VERSION 5.7 ;
  NOWIREEXTENSIONATPIN ON ;
  DIVIDERCHAR "/" ;
  BUSBITCHARS "[]" ;
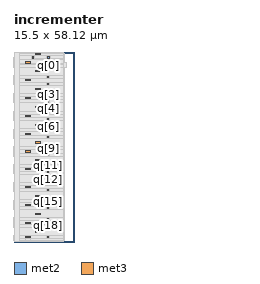
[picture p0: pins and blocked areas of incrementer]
MACRO incrementer
  CLASS BLOCK ;
  FOREIGN incrementer ;
  ORIGIN 0.000 0.000 ;
  SIZE 15.500 BY 58.120 ;
  PIN q[18]
    DIRECTION OUTPUT ;
    USE SIGNAL ;
    ANTENNAGATEAREA 0.235500 ;
    ANTENNADIFFAREA 1.339600 ;
    PORT
      LAYER met2 ;
        RECT 10.320 4.730 10.700 5.110 ;
    END
  END q[18]
  PIN q[19]
    DIRECTION OUTPUT ;
    USE SIGNAL ;
    ANTENNAGATEAREA 0.235500 ;
    ANTENNADIFFAREA 1.339600 ;
    PORT
      LAYER met2 ;
        RECT 10.320 1.330 10.700 1.710 ;
    END
  END q[19]
  PIN q[16]
    DIRECTION OUTPUT ;
    USE SIGNAL ;
    ANTENNAGATEAREA 0.235500 ;
    ANTENNADIFFAREA 1.339600 ;
    PORT
      LAYER met2 ;
        RECT 10.320 10.170 10.700 10.550 ;
    END
  END q[16]
  PIN q[17]
    DIRECTION OUTPUT ;
    USE SIGNAL ;
    ANTENNAGATEAREA 0.235500 ;
    ANTENNADIFFAREA 1.339600 ;
    PORT
      LAYER met2 ;
        RECT 10.320 6.770 10.700 7.150 ;
    END
  END q[17]
  PIN q[14]
    DIRECTION OUTPUT ;
    USE SIGNAL ;
    ANTENNAGATEAREA 0.235500 ;
    ANTENNADIFFAREA 1.339600 ;
    PORT
      LAYER met2 ;
        RECT 10.320 15.610 10.700 15.990 ;
    END
  END q[14]
  PIN q[15]
    DIRECTION OUTPUT ;
    USE SIGNAL ;
    ANTENNAGATEAREA 0.235500 ;
    ANTENNADIFFAREA 1.339600 ;
    PORT
      LAYER met2 ;
        RECT 10.320 12.210 10.700 12.590 ;
    END
  END q[15]
  PIN q[12]
    DIRECTION OUTPUT ;
    USE SIGNAL ;
    ANTENNAGATEAREA 0.235500 ;
    ANTENNADIFFAREA 1.339600 ;
    PORT
      LAYER met2 ;
        RECT 10.320 21.050 10.700 21.430 ;
    END
  END q[12]
  PIN q[13]
    DIRECTION OUTPUT ;
    USE SIGNAL ;
    ANTENNAGATEAREA 0.235500 ;
    ANTENNADIFFAREA 1.339600 ;
    PORT
      LAYER met2 ;
        RECT 10.320 17.650 10.700 18.030 ;
    END
  END q[13]
  PIN q[10]
    DIRECTION OUTPUT ;
    USE SIGNAL ;
    ANTENNAGATEAREA 0.235500 ;
    ANTENNADIFFAREA 1.339600 ;
    PORT
      LAYER met2 ;
        RECT 10.320 26.490 10.700 26.870 ;
    END
  END q[10]
  PIN q[11]
    DIRECTION OUTPUT ;
    USE SIGNAL ;
    ANTENNAGATEAREA 0.235500 ;
    ANTENNADIFFAREA 1.339600 ;
    PORT
      LAYER met2 ;
        RECT 10.320 23.090 10.700 23.470 ;
    END
  END q[11]
  PIN q[8]
    DIRECTION OUTPUT ;
    USE SIGNAL ;
    ANTENNAGATEAREA 0.235500 ;
    ANTENNADIFFAREA 1.339600 ;
    PORT
      LAYER met2 ;
        RECT 10.320 31.930 10.700 32.310 ;
    END
  END q[8]
  PIN q[9]
    DIRECTION OUTPUT ;
    USE SIGNAL ;
    ANTENNAGATEAREA 0.235500 ;
    ANTENNADIFFAREA 1.339600 ;
    PORT
      LAYER met2 ;
        RECT 10.320 28.530 10.700 28.910 ;
    END
  END q[9]
  PIN q[6]
    DIRECTION OUTPUT ;
    USE SIGNAL ;
    ANTENNAGATEAREA 0.235500 ;
    ANTENNADIFFAREA 1.339600 ;
    PORT
      LAYER met2 ;
        RECT 10.320 37.370 10.700 37.750 ;
    END
  END q[6]
  PIN q[7]
    DIRECTION OUTPUT ;
    USE SIGNAL ;
    ANTENNAGATEAREA 0.235500 ;
    ANTENNADIFFAREA 1.339600 ;
    PORT
      LAYER met2 ;
        RECT 10.320 33.970 10.700 34.350 ;
    END
  END q[7]
  PIN q[4]
    DIRECTION OUTPUT ;
    USE SIGNAL ;
    ANTENNAGATEAREA 0.235500 ;
    ANTENNADIFFAREA 1.339600 ;
    PORT
      LAYER met2 ;
        RECT 10.320 42.810 10.700 43.190 ;
    END
  END q[4]
  PIN q[5]
    DIRECTION OUTPUT ;
    USE SIGNAL ;
    ANTENNAGATEAREA 0.235500 ;
    ANTENNADIFFAREA 1.339600 ;
    PORT
      LAYER met2 ;
        RECT 10.320 39.410 10.700 39.790 ;
    END
  END q[5]
  PIN q[2]
    DIRECTION OUTPUT ;
    USE SIGNAL ;
    ANTENNAGATEAREA 0.235500 ;
    ANTENNADIFFAREA 1.339600 ;
    PORT
      LAYER met2 ;
        RECT 10.320 48.250 10.700 48.630 ;
    END
  END q[2]
  PIN q[3]
    DIRECTION OUTPUT ;
    USE SIGNAL ;
    ANTENNAGATEAREA 0.235500 ;
    ANTENNADIFFAREA 1.339600 ;
    PORT
      LAYER met2 ;
        RECT 10.320 44.850 10.700 45.230 ;
    END
  END q[3]
  PIN q[0]
    DIRECTION OUTPUT ;
    USE SIGNAL ;
    ANTENNAGATEAREA 0.235500 ;
    ANTENNADIFFAREA 1.339600 ;
    PORT
      LAYER met2 ;
        RECT 10.320 53.690 10.700 54.070 ;
    END
  END q[0]
  PIN q[1]
    DIRECTION OUTPUT ;
    USE SIGNAL ;
    ANTENNAGATEAREA 0.235500 ;
    ANTENNADIFFAREA 1.339600 ;
    PORT
      LAYER met2 ;
        RECT 10.320 50.290 10.700 50.670 ;
    END
  END q[1]
  PIN VPWR
    USE POWER ;
    PORT
      LAYER met3 ;
        RECT 3.500 1.330 5.200 1.670 ;
    END
    PORT
      LAYER met3 ;
        RECT 3.500 5.770 5.200 6.110 ;
    END
    PORT
      LAYER met3 ;
        RECT 3.500 11.210 5.200 11.550 ;
    END
    PORT
      LAYER met3 ;
        RECT 3.500 16.650 5.200 16.990 ;
    END
    PORT
      LAYER met3 ;
        RECT 3.500 22.090 5.200 22.430 ;
    END
    PORT
      LAYER met3 ;
        RECT 3.500 27.530 5.200 27.870 ;
    END
    PORT
      LAYER met3 ;
        RECT 3.500 32.970 5.200 33.310 ;
    END
    PORT
      LAYER met3 ;
        RECT 3.500 38.410 5.200 38.750 ;
    END
    PORT
      LAYER met3 ;
        RECT 3.500 43.850 5.200 44.190 ;
    END
    PORT
      LAYER met3 ;
        RECT 3.500 49.290 5.200 49.630 ;
    END
    PORT
      LAYER met3 ;
        RECT 3.500 54.730 5.200 55.070 ;
    END
  END VPWR
  PIN VGND
    USE GROUND ;
    PORT
      LAYER met3 ;
        RECT 6.500 3.050 8.200 3.390 ;
    END
    PORT
      LAYER met3 ;
        RECT 6.500 8.490 8.200 8.830 ;
    END
    PORT
      LAYER met3 ;
        RECT 6.500 13.930 8.200 14.270 ;
    END
    PORT
      LAYER met3 ;
        RECT 6.500 19.370 8.200 19.710 ;
    END
    PORT
      LAYER met3 ;
        RECT 6.500 24.810 8.200 25.150 ;
    END
    PORT
      LAYER met3 ;
        RECT 6.500 30.250 8.200 30.590 ;
    END
    PORT
      LAYER met3 ;
        RECT 6.500 35.690 8.200 36.030 ;
    END
    PORT
      LAYER met3 ;
        RECT 6.500 41.130 8.200 41.470 ;
    END
    PORT
      LAYER met3 ;
        RECT 6.500 46.570 8.200 46.910 ;
    END
    PORT
      LAYER met3 ;
        RECT 6.500 52.010 8.200 52.350 ;
    END
    PORT
      LAYER met3 ;
        RECT 6.500 57.450 8.200 57.790 ;
    END
  END VGND
  PIN clk
    DIRECTION INPUT ;
    USE CLOCK ;
    ANTENNAGATEAREA 0.426000 ;
    PORT
      LAYER met2 ;
        RECT 5.760 56.250 6.100 56.770 ;
    END
  END clk
  PIN rst_n
    DIRECTION INPUT ;
    USE SIGNAL ;
    ANTENNAGATEAREA 0.495000 ;
    PORT
      LAYER met2 ;
        RECT 10.120 56.270 10.770 56.820 ;
    END
  END rst_n
  PIN inc
    DIRECTION INPUT ;
    USE SIGNAL ;
    ANTENNAGATEAREA 0.471000 ;
    ANTENNADIFFAREA 0.275500 ;
    PORT
      LAYER met2 ;
        RECT 13.200 54.980 13.620 55.400 ;
    END
  END inc
  OBS
      LAYER nwell ;
        RECT 0.000 56.315 15.500 57.705 ;
        RECT -0.070 55.040 15.500 56.315 ;
        RECT -0.070 53.490 16.000 55.040 ;
        RECT -0.070 53.485 15.500 53.490 ;
        RECT 0.000 50.875 15.500 53.485 ;
        RECT -0.070 48.045 15.500 50.875 ;
        RECT 0.000 45.435 15.500 48.045 ;
        RECT -0.070 42.605 15.500 45.435 ;
        RECT 0.000 39.995 15.500 42.605 ;
        RECT -0.070 37.165 15.500 39.995 ;
        RECT 0.000 34.555 15.500 37.165 ;
        RECT -0.070 31.725 15.500 34.555 ;
        RECT 0.000 29.115 15.500 31.725 ;
        RECT -0.070 26.285 15.500 29.115 ;
        RECT 0.000 23.675 15.500 26.285 ;
        RECT -0.070 20.845 15.500 23.675 ;
        RECT 0.000 18.235 15.500 20.845 ;
        RECT -0.070 15.405 15.500 18.235 ;
        RECT 0.000 12.795 15.500 15.405 ;
        RECT -0.070 9.965 15.500 12.795 ;
        RECT 0.000 7.355 15.500 9.965 ;
        RECT -0.070 4.525 15.500 7.355 ;
        RECT 0.000 1.915 15.500 4.525 ;
        RECT -0.070 0.310 15.500 1.915 ;
      LAYER li1 ;
        RECT 0.120 0.410 15.035 57.705 ;
      LAYER met1 ;
        RECT 0.120 0.260 15.005 57.860 ;
      LAYER met2 ;
        RECT 1.590 57.100 15.035 57.790 ;
        RECT 1.590 57.050 9.840 57.100 ;
        RECT 1.590 55.970 5.480 57.050 ;
        RECT 6.380 55.990 9.840 57.050 ;
        RECT 11.050 55.990 15.035 57.100 ;
        RECT 6.380 55.970 15.035 55.990 ;
        RECT 1.590 55.680 15.035 55.970 ;
        RECT 1.590 54.700 12.920 55.680 ;
        RECT 13.900 54.700 15.035 55.680 ;
        RECT 1.590 54.350 15.035 54.700 ;
        RECT 1.590 53.410 10.040 54.350 ;
        RECT 10.980 53.410 15.035 54.350 ;
        RECT 1.590 50.950 15.035 53.410 ;
        RECT 1.590 50.010 10.040 50.950 ;
        RECT 10.980 50.010 15.035 50.950 ;
        RECT 1.590 48.910 15.035 50.010 ;
        RECT 1.590 47.970 10.040 48.910 ;
        RECT 10.980 47.970 15.035 48.910 ;
        RECT 1.590 45.510 15.035 47.970 ;
        RECT 1.590 44.570 10.040 45.510 ;
        RECT 10.980 44.570 15.035 45.510 ;
        RECT 1.590 43.470 15.035 44.570 ;
        RECT 1.590 42.530 10.040 43.470 ;
        RECT 10.980 42.530 15.035 43.470 ;
        RECT 1.590 40.070 15.035 42.530 ;
        RECT 1.590 39.130 10.040 40.070 ;
        RECT 10.980 39.130 15.035 40.070 ;
        RECT 1.590 38.030 15.035 39.130 ;
        RECT 1.590 37.090 10.040 38.030 ;
        RECT 10.980 37.090 15.035 38.030 ;
        RECT 1.590 34.630 15.035 37.090 ;
        RECT 1.590 33.690 10.040 34.630 ;
        RECT 10.980 33.690 15.035 34.630 ;
        RECT 1.590 32.590 15.035 33.690 ;
        RECT 1.590 31.650 10.040 32.590 ;
        RECT 10.980 31.650 15.035 32.590 ;
        RECT 1.590 29.190 15.035 31.650 ;
        RECT 1.590 28.250 10.040 29.190 ;
        RECT 10.980 28.250 15.035 29.190 ;
        RECT 1.590 27.150 15.035 28.250 ;
        RECT 1.590 26.210 10.040 27.150 ;
        RECT 10.980 26.210 15.035 27.150 ;
        RECT 1.590 23.750 15.035 26.210 ;
        RECT 1.590 22.810 10.040 23.750 ;
        RECT 10.980 22.810 15.035 23.750 ;
        RECT 1.590 21.710 15.035 22.810 ;
        RECT 1.590 20.770 10.040 21.710 ;
        RECT 10.980 20.770 15.035 21.710 ;
        RECT 1.590 18.310 15.035 20.770 ;
        RECT 1.590 17.370 10.040 18.310 ;
        RECT 10.980 17.370 15.035 18.310 ;
        RECT 1.590 16.270 15.035 17.370 ;
        RECT 1.590 15.330 10.040 16.270 ;
        RECT 10.980 15.330 15.035 16.270 ;
        RECT 1.590 12.870 15.035 15.330 ;
        RECT 1.590 11.930 10.040 12.870 ;
        RECT 10.980 11.930 15.035 12.870 ;
        RECT 1.590 10.830 15.035 11.930 ;
        RECT 1.590 9.890 10.040 10.830 ;
        RECT 10.980 9.890 15.035 10.830 ;
        RECT 1.590 7.430 15.035 9.890 ;
        RECT 1.590 6.490 10.040 7.430 ;
        RECT 10.980 6.490 15.035 7.430 ;
        RECT 1.590 5.390 15.035 6.490 ;
        RECT 1.590 4.450 10.040 5.390 ;
        RECT 10.980 4.450 15.035 5.390 ;
        RECT 1.590 1.990 15.035 4.450 ;
        RECT 1.590 1.050 10.040 1.990 ;
        RECT 10.980 1.050 15.035 1.990 ;
        RECT 1.590 0.330 15.035 1.050 ;
      LAYER met3 ;
        RECT 3.500 0.330 5.200 0.930 ;
  END
END incrementer
END LIBRARY

